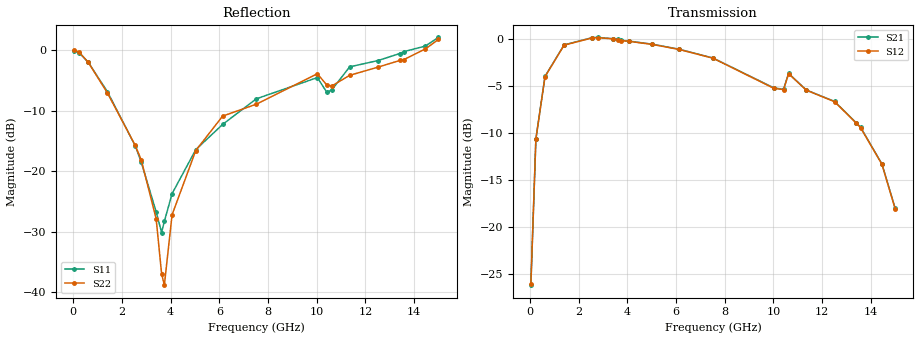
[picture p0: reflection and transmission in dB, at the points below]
! VJ1111D2R0BXR
! DATE 03/08/2022  10:53
! CAPACITORS MOUNTED IN SERIES ON 25 MIL THICK MICROSTRIP SUBSTRATE
# GHz  S  MA  R  50.00
!  FREQ  S11M  S11A  S21M  S21A  S12M  S12A  S22M  S22A
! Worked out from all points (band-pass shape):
!   801 points, 40 MHz to 15 GHz, reference 50 ohm
!   highest |S21| = 0.14 dB at 2.789 GHz (marker M1); lowest = -26.1 dB at 40 MHz (marker M2)
!   |S21| within 3 dB of the highest: 766.4 MHz to 8.617 GHz (7.851 GHz wide, 167 % of centre)
!   lowest |S11| = -30.1 dB at 3.63 GHz (marker M3), VSWR 1.06, Z = 47.1 - j0.701 ohm
!   |S11| at or under -10 dB: 1.851 GHz to 6.917 GHz (5.066 GHz wide, 116 % of centre)
!   |S22| runs from -39.0 to 1.8 dB; largest |S21 - S12| = 0.0066
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0.04  0.9963 -2.9  0.04927 86.6  0.04996 86.7  1.005 -2.7
0.2457  0.9558 -16.6  0.2933 73.8  0.2933 73.9  0.9623 -16.6
0.6197  0.7951 -38.0  0.6309 53.6  0.6284 53.5  0.7938 -38.0
1.4051  0.4544 -64.7  0.9267 29.0  0.924 29.1  0.4435 -66.1
2.5458  0.1627 -85.7  1.012 13.0  1.009 13.0  0.1636 -88.8
2.7889  0.1197 -89.5  1.016 10.8  1.013 10.8  0.1248 -91.9
3.406  0.04623 -120.3  0.9996 6.0  0.9978 6.0  0.04051 -107.8
3.6304  0.03113 -166.2  0.9917 4.6  0.9873 4.7  0.01416 -128.2
3.7426  0.03854 171.5  0.9802 3.6  0.9777 3.7  0.01145 -153.7
4.0605  0.0654 113.4  0.9713 2.7  0.9683 2.8  0.04374 94.2
5.0329  0.1509 87.6  0.935 -2.4  0.9321 -2.3  0.1484 71.9
6.1362  0.244 78.1  0.8791 -8.9  0.8763 -8.7  0.2858 62.2
7.52  0.3973 65.2  0.7895 -15.2  0.7878 -15.0  0.3585 54.9
10.0258  0.5949 44.6  0.5481 -26.6  0.5446 -26.5  0.64 34.8
10.4185  0.4491 32.0  0.539 -5.3  0.5372 -5.0  0.5156 18.1
10.6242  0.4726 54.3  0.6547 -16.4  0.6516 -16.0  0.5081 34.7
11.3535  0.7297 50.5  0.534 -29.7  0.5331 -29.5  0.6212 24.7
12.5129  0.8222 33.0  0.4647 -34.7  0.463 -34.5  0.7257 34.6
13.4105  0.9406 26.2  0.3572 -41.3  0.3556 -41.0  0.8241 29.7
13.5788  0.9755 -153.0  0.3393 -42.4  0.3374 -41.9  0.8378 -152.9
14.4577  1.083 -151.7  0.2165 -46.8  0.2157 -46.3  1.026 -165.5
15  1.279 -160.8  0.1261 -32.7  0.1254 -32.1  1.229 -171.6
